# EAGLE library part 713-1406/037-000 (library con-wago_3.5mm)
Serie 713, Stiftleiste (für Leiterplatten) Einlötstift gerade 0,8 x 0,8 mm / Series 713, Male header (for PCBs) Straight solder pin 0.8 x 0.8 mm Polzahl / Pole No.: 12 Bemessungsspannung / Rated Voltage: 160 V Nennstrom / Nominal Current: 10 A Lötstiftlänge: / Solder Pin Length: 3.8 mm Farbe / Color: schwarz / black Stand: 01.01.2012. Die jeweils aktuellen Daten zu diesem Artikel finden Sie in unserem Produktkatalog, den Sie unter www.wago.com einsehen können. As of: 01/01/2012. Please find the newest data for this article in our product catalogue, which can be viewed under www.wago.com.

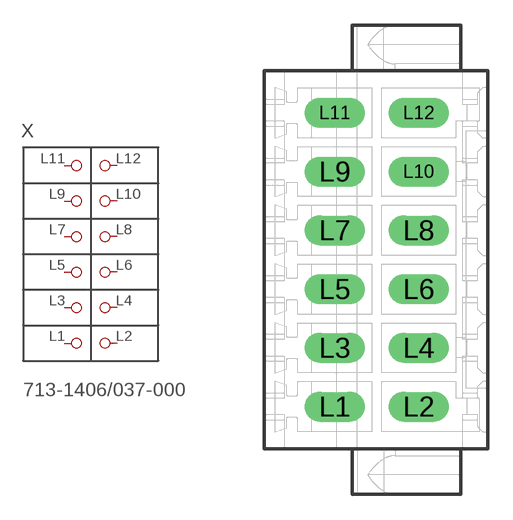
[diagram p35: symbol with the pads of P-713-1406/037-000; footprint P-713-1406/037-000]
Designator prefix X

## 713-1406/037-000  [P-713-1406/037-000]
L1  L1
L2  L2
L3  L3
L4  L4
L5  L5
L6  L6
L7  L7
L8  L8
L9  L9
L10  L10
L11  L11
L12  L12

## Footprint P-713-1406/037-000 (pad centres in mm)
drill 1.2 long: L1 -2.45,-8.75; L2 2.55,-8.75; L3 -2.45,-5.25; L4 2.55,-5.25; L5 -2.45,-1.75; L6 2.55,-1.75; L7 -2.45,1.75; L8 2.55,1.75; L9 -2.45,5.25; L10 2.55,5.25; L11 -2.45,8.75; L12 2.55,8.75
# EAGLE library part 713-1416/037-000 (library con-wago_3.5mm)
Serie 713, Stiftleiste (für Leiterplatten) Einlötstift gerade 0,8 x 0,8 mm / Series 713, Male header (for PCBs) Straight solder pin 0.8 x 0.8 mm Polzahl / Pole No.: 32 Bemessungsspannung / Rated Voltage: 160 V Nennstrom / Nominal Current: 10 A Lötstiftlänge: / Solder Pin Length: 3.8 mm Farbe / Color: schwarz / black Stand: 01.01.2012. Die jeweils aktuellen Daten zu diesem Artikel finden Sie in unserem Produktkatalog, den Sie unter www.wago.com einsehen können. As of: 01/01/2012. Please find the newest data for this article in our product catalogue, which can be viewed under www.wago.com.

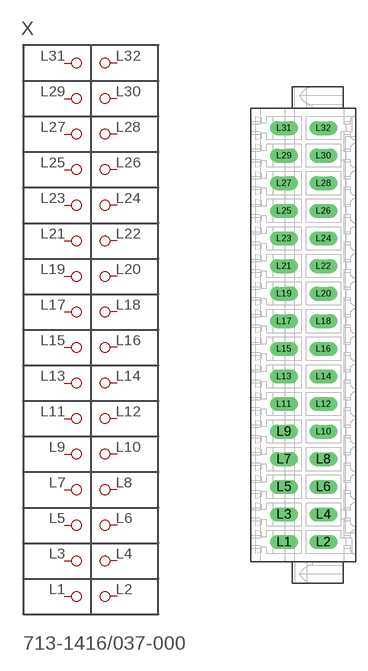
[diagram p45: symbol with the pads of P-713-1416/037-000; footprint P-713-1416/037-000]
Designator prefix X

## 713-1416/037-000  [P-713-1416/037-000]
L1  L1
L2  L2
L3  L3
L4  L4
L5  L5
L6  L6
L7  L7
L8  L8
L9  L9
L10  L10
L11  L11
L12  L12
L13  L13
L14  L14
L15  L15
L16  L16
L17  L17
L18  L18
L19  L19
L20  L20
L21  L21
L22  L22
L23  L23
L24  L24
L25  L25
L26  L26
L27  L27
L28  L28
L29  L29
L30  L30
L31  L31
L32  L32

## Footprint P-713-1416/037-000 (pad centres in mm)
drill 1.2 long: L1 -2.45,-26.25; L2 2.55,-26.25; L3 -2.45,-22.75; L4 2.55,-22.75; L5 -2.45,-19.25; L6 2.55,-19.25; L7 -2.45,-15.75; L8 2.55,-15.75; L9 -2.45,-12.25; L10 2.55,-12.25; L11 -2.45,-8.75; L12 2.55,-8.75; L13 -2.45,-5.25; L14 2.55,-5.25; L15 -2.45,-1.75; L16 2.55,-1.75; L17 -2.45,1.75; L18 2.55,1.75; L19 -2.45,5.25; L20 2.55,5.25; L21 -2.45,8.75; L22 2.55,8.75; L23 -2.45,12.25; L24 2.55,12.25; L25 -2.45,15.75; L26 2.55,15.75; L27 -2.45,19.25; L28 2.55,19.25; L29 -2.45,22.75; L30 2.55,22.75; L31 -2.45,26.25; L32 2.55,26.25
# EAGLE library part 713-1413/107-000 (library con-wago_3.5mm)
Serie 713, Stiftleiste (für Leiterplatten) Einlötstift gerade 0,8 x 0,8 mm / Series 713, Male header (for PCBs) Straight solder pin 0.8 x 0.8 mm Polzahl / Pole No.: 26 Bemessungsspannung / Rated Voltage: 160 V Nennstrom / Nominal Current: 10 A Lötstiftlänge: / Solder Pin Length: 3.8 mm Farbe / Color: schwarz / black Stand: 01.01.2012. Die jeweils aktuellen Daten zu diesem Artikel finden Sie in unserem Produktkatalog, den Sie unter www.wago.com einsehen können. As of: 01/01/2012. Please find the newest data for this article in our product catalogue, which can be viewed under www.wago.com.

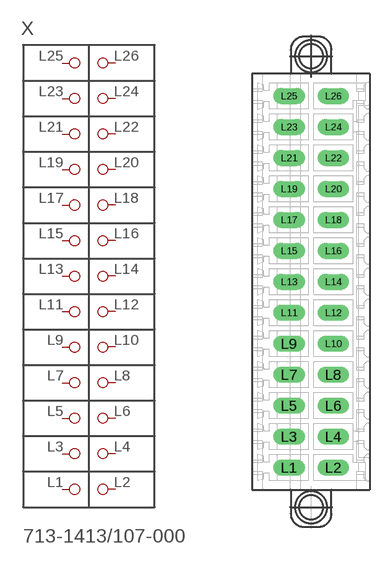
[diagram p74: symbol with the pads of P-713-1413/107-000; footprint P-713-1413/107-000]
Designator prefix X

## 713-1413/107-000  [P-713-1413/107-000]
L1  L1
L2  L2
L3  L3
L4  L4
L5  L5
L6  L6
L7  L7
L8  L8
L9  L9
L10  L10
L11  L11
L12  L12
L13  L13
L14  L14
L15  L15
L16  L16
L17  L17
L18  L18
L19  L19
L20  L20
L21  L21
L22  L22
L23  L23
L24  L24
L25  L25
L26  L26

## Footprint P-713-1413/107-000 (pad centres in mm)
drill 1.2 long: L1 -2.45,-21; L2 2.55,-21; L3 -2.45,-17.5; L4 2.55,-17.5; L5 -2.45,-14; L6 2.55,-14; L7 -2.45,-10.5; L8 2.55,-10.5; L9 -2.45,-7; L10 2.55,-7; L11 -2.45,-3.5; L12 2.55,-3.5; L13 -2.45,0; L14 2.55,0; L15 -2.45,3.5; L16 2.55,3.5; L17 -2.45,7; L18 2.55,7; L19 -2.45,10.5; L20 2.55,10.5; L21 -2.45,14; L22 2.55,14; L23 -2.45,17.5; L24 2.55,17.5; L25 -2.45,21; L26 2.55,21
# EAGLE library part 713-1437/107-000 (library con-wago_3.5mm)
Serie 713, Stiftleiste (für Leiterplatten) Einlötstift abgewinkelt 0,8 x 0,8 mm / Series 713, Male header (for PCBs) Angled solder pin 0.8 x 0.8 mm Polzahl / Pole No.: 34 Bemessungsspannung / Rated Voltage: 160 V Nennstrom / Nominal Current: 10 A Lötstiftlänge: / Solder Pin Length: 3.8 mm Farbe / Color: schwarz / black Stand: 01.01.2012. Die jeweils aktuellen Daten zu diesem Artikel finden Sie in unserem Produktkatalog, den Sie unter www.wago.com einsehen können. As of: 01/01/2012. Please find the newest data for this article in our product catalogue, which can be viewed under www.wago.com.

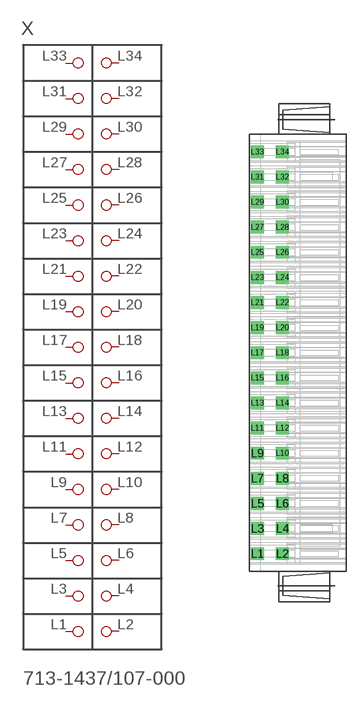
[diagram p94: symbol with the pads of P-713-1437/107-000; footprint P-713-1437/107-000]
Designator prefix X

## 713-1437/107-000  [P-713-1437/107-000]
L1  L1
L2  L2
L3  L3
L4  L4
L5  L5
L6  L6
L7  L7
L8  L8
L9  L9
L10  L10
L11  L11
L12  L12
L13  L13
L14  L14
L15  L15
L16  L16
L17  L17
L18  L18
L19  L19
L20  L20
L21  L21
L22  L22
L23  L23
L24  L24
L25  L25
L26  L26
L27  L27
L28  L28
L29  L29
L30  L30
L31  L31
L32  L32
L33  L33
L34  L34

## Footprint P-713-1437/107-000 (pad centres in mm)
drill 1.2 square: L1 -5.65,-28; L2 -2.15,-28; L3 -5.65,-24.5; L4 -2.15,-24.5; L5 -5.65,-21; L6 -2.15,-21; L7 -5.65,-17.5; L8 -2.15,-17.5; L9 -5.65,-14; L10 -2.15,-14; L11 -5.65,-10.5; L12 -2.15,-10.5; L13 -5.65,-7; L14 -2.15,-7; L15 -5.65,-3.5; L16 -2.15,-3.5; L17 -5.65,0; L18 -2.15,0; L19 -5.65,3.5; L20 -2.15,3.5; L21 -5.65,7; L22 -2.15,7; L23 -5.65,10.5; L24 -2.15,10.5; L25 -5.65,14; L26 -2.15,14; L27 -5.65,17.5; L28 -2.15,17.5; L29 -5.65,21; L30 -2.15,21; L31 -5.65,24.5; L32 -2.15,24.5; L33 -5.65,28; L34 -2.15,28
